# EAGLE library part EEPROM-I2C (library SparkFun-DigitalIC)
I2C EEPROM chips, 24LC256 (and others)

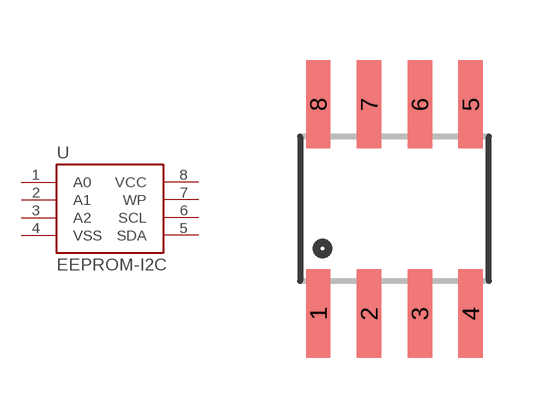
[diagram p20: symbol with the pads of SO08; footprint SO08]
Designator prefix -

## EEPROM-I2CSMD  [SO08]
1  A0
2  A1
3  A2
4  VSS  pwr
5  SDA
6  SCL
7  WP
8  VCC  pwr

## Footprint SO08 (pad centres in mm)
Small Outline Package Fits JEDEC packages (narrow SOIC-8)
smd 0.61 x 2.21: 1 -1.905,-2.616; 2 -0.635,-2.616; 3 0.635,-2.616; 4 1.905,-2.616; 5 1.905,2.616; 6 0.635,2.616; 7 -0.635,2.616; 8 -1.905,2.616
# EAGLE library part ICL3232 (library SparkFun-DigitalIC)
3V to RS-232 transceiver

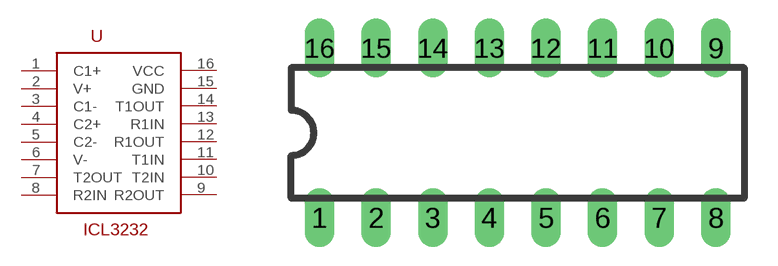
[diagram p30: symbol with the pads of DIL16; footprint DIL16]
Designator prefix -

## ICL3232  [DIL16]
1  C1+
2  V+
3  C1-
4  C2+
5  C2-
6  V-
7  T2OUT
8  R2IN
9  R2OUT
10  T2IN
11  T1IN
12  R1OUT
13  R1IN
14  T1OUT
15  GND
16  VCC

## Footprint DIL16 (pad centres in mm)
Dual In Line Package
drill 0.813 long: 1 -8.89,-3.81; 2 -6.35,-3.81; 3 -3.81,-3.81; 4 -1.27,-3.81; 5 1.27,-3.81; 6 3.81,-3.81; 7 6.35,-3.81; 8 8.89,-3.81; 9 8.89,3.81; 10 6.35,3.81; 11 3.81,3.81; 12 1.27,3.81; 13 -1.27,3.81; 14 -3.81,3.81; 15 -6.35,3.81; 16 -8.89,3.81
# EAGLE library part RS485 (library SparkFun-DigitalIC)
RS485 transceiver

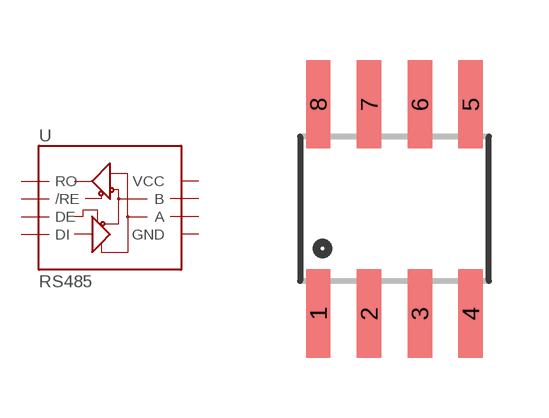
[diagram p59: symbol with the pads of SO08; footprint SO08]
Designator prefix -

## RS485SOIC  [SO08]
1  RO
2  /RE
3  DE
4  DI
5  GND
6  A
7  B
8  VCC

## Footprint SO08 (pad centres in mm)
Small Outline Package Fits JEDEC packages (narrow SOIC-8)
smd 0.61 x 2.21: 1 -1.905,-2.616; 2 -0.635,-2.616; 3 0.635,-2.616; 4 1.905,-2.616; 5 1.905,2.616; 6 0.635,2.616; 7 -0.635,2.616; 8 -1.905,2.616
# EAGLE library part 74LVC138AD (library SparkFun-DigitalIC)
3-to-8 decoder

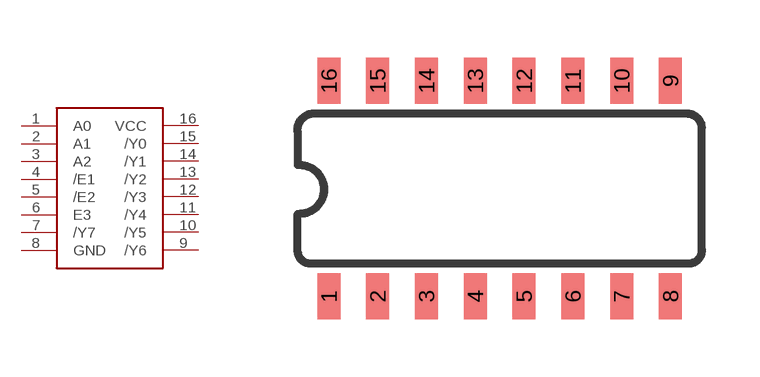
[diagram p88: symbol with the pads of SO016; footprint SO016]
Designator prefix -

## 74LVC138AD  [SO016]
1  A0
2  A1
3  A2
4  /E1
5  /E2
6  E3
7  /Y7
8  GND
9  /Y6
10  /Y5
11  /Y4
12  /Y3
13  /Y2
14  /Y1
15  /Y0
16  VCC

## Footprint SO016 (pad centres in mm)
smd 0.6 x 1.2: 1 -4.445,-2.8; 2 -3.175,-2.8; 3 -1.905,-2.8; 4 -0.635,-2.8; 5 0.635,-2.8; 6 1.905,-2.8; 7 3.175,-2.8; 8 4.445,-2.8; 9 4.445,2.8; 10 3.175,2.8; 11 1.905,2.8; 12 0.635,2.8; 13 -0.635,2.8; 14 -1.905,2.8; 15 -3.175,2.8; 16 -4.445,2.8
